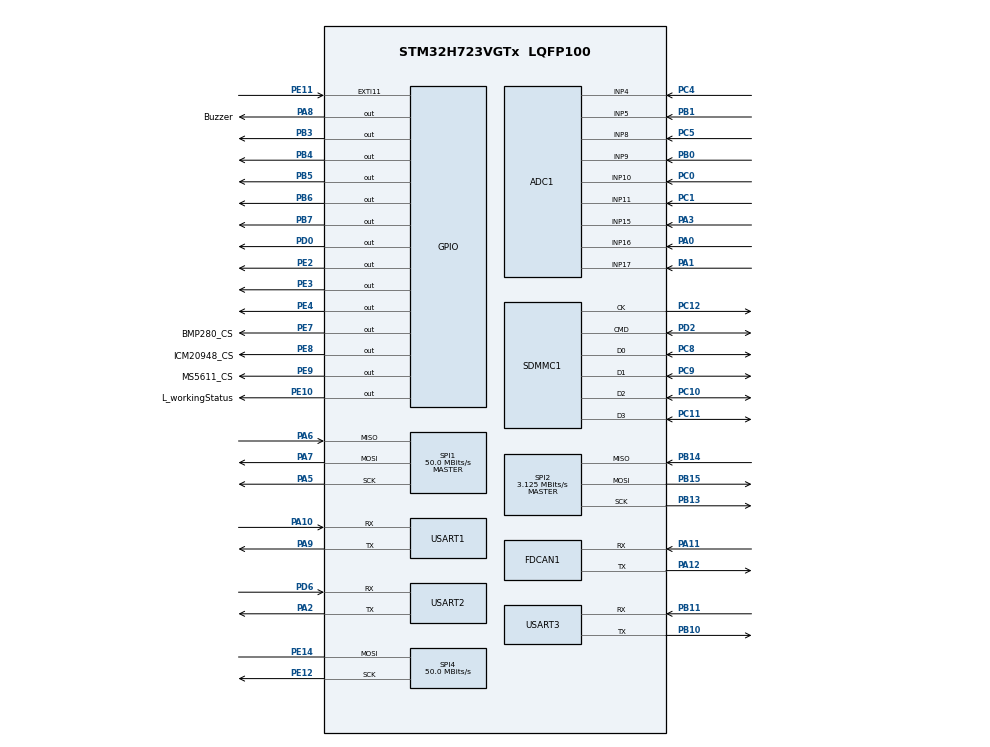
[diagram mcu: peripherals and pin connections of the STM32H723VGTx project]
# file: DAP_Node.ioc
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ADC1.Channel-1\#ChannelRegularConversion=ADC_CHANNEL_10
ADC1.NbrOfConversionFlag=1
ADC1.OffsetNumber-1\#ChannelRegularConversion=ADC_OFFSET_NONE
ADC1.OffsetSignedSaturation-1\#ChannelRegularConversion=DISABLE
ADC1.Rank-1\#ChannelRegularConversion=1
ADC1.SamplingTime-1\#ChannelRegularConversion=ADC_SAMPLETIME_1CYCLE_5
ADC1.master=1
ADC2.Channel-1\#ChannelRegularConversion=ADC_CHANNEL_11
ADC2.NbrOfConversionFlag=1
ADC2.OffsetNumber-1\#ChannelRegularConversion=ADC_OFFSET_NONE
ADC2.OffsetSignedSaturation-1\#ChannelRegularConversion=DISABLE
ADC2.Rank-1\#ChannelRegularConversion=1
ADC2.Resolution=ADC_RESOLUTION_16B
ADC2.SamplingTime-1\#ChannelRegularConversion=ADC_SAMPLETIME_1CYCLE_5
CORTEX_M7.default_mode_Activation=1
FDCAN1.CalculateBaudRateNominal=520833
FDCAN1.CalculateTimeBitNominal=1920
FDCAN1.CalculateTimeQuantumNominal=640.0
Mcu.Family=STM32H7
Mcu.Name=STM32H723VGTx
Mcu.Package=LQFP100
NVIC.PriorityGroup=NVIC_PRIORITYGROUP_4
PA0.Mode=IN16-Single-Ended
PA0.Signal=ADC1_INP16
PA1.Mode=IN17-Single-Ended
PA1.Signal=ADC1_INP17
PA10.Mode=Asynchronous
PA10.Signal=USART1_RX
PA11.Mode=FDCAN_Activate
PA11.Signal=FDCAN1_RX
PA12.Mode=FDCAN_Activate
PA12.Signal=FDCAN1_TX
PA13(JTMS/SWDIO).Mode=Serial_Wire
PA13(JTMS/SWDIO).Signal=DEBUG_JTMS-SWDIO
PA14(JTCK/SWCLK).Mode=Serial_Wire
PA14(JTCK/SWCLK).Signal=DEBUG_JTCK-SWCLK
PA2.Mode=Asynchronous
PA2.Signal=USART2_TX
PA3.Signal=ADCx_INP15
PA5.GPIO_Speed=GPIO_SPEED_FREQ_VERY_HIGH
PA5.Mode=Full_Duplex_Master
PA5.Signal=SPI1_SCK
PA6.GPIO_Speed=GPIO_SPEED_FREQ_VERY_HIGH
PA6.Mode=Full_Duplex_Master
PA6.Signal=SPI1_MISO
PA7.GPIO_Speed=GPIO_SPEED_FREQ_VERY_HIGH
PA7.Mode=Full_Duplex_Master
PA7.Signal=SPI1_MOSI
PA8.GPIO_Label=Buzzer
PA8.Signal=GPIO_Output
PA9.Mode=Asynchronous
PA9.Signal=USART1_TX
PB0.Signal=ADCx_INP9
PB1.Signal=ADCx_INP5
PB10.Mode=Asynchronous
PB10.Signal=USART3_TX
PB11.Mode=Asynchronous
PB11.Signal=USART3_RX
PB13.GPIO_Speed=GPIO_SPEED_FREQ_VERY_HIGH
PB13.Mode=Full_Duplex_Master
PB13.Signal=SPI2_SCK
PB14.GPIO_Speed=GPIO_SPEED_FREQ_VERY_HIGH
PB14.Mode=Full_Duplex_Master
PB14.Signal=SPI2_MISO
PB15.GPIO_Speed=GPIO_SPEED_FREQ_VERY_HIGH
PB15.Mode=Full_Duplex_Master
PB15.Signal=SPI2_MOSI
PB3(JTDO/TRACESWO).Signal=GPIO_Output
PB4(NJTRST).Signal=GPIO_Output
PB5.Signal=GPIO_Output
PB6.Signal=GPIO_Output
PB7.Signal=GPIO_Output
PC0.Signal=ADCx_INP10
PC1.Signal=SharedAnalog_PC1
PC10.Mode=SD_4_bits_Wide_bus
PC10.Signal=SDMMC1_D2
PC11.Mode=SD_4_bits_Wide_bus
PC11.Signal=SDMMC1_D3
PC12.Mode=SD_4_bits_Wide_bus
PC12.Signal=SDMMC1_CK
PC14-OSC32_IN.Mode=LSE-External-Oscillator
PC14-OSC32_IN.Signal=RCC_OSC32_IN
PC15-OSC32_OUT.Mode=LSE-External-Oscillator
PC15-OSC32_OUT.Signal=RCC_OSC32_OUT
PC4.Signal=ADCx_INP4
PC5.Signal=ADCx_INP8
PC8.Mode=SD_4_bits_Wide_bus
PC8.Signal=SDMMC1_D0
PC9.Mode=SD_4_bits_Wide_bus
PC9.Signal=SDMMC1_D1
PD0.GPIO_Speed=GPIO_SPEED_FREQ_VERY_HIGH
PD0.PinState=GPIO_PIN_SET
PD0.Signal=GPIO_Output
PD2.Mode=SD_4_bits_Wide_bus
PD2.Signal=SDMMC1_CMD
PD6.Mode=Asynchronous
PD6.Signal=USART2_RX
PE10.GPIO_Label=L_workingStatus
PE10.Signal=GPIO_Output
PE11.Signal=GPXTI11
PE12.Mode=Simplex_Bidirectional_Master
PE12.Signal=SPI4_SCK
PE14.Mode=Simplex_Bidirectional_Master
PE14.Signal=SPI4_MOSI
PE2.Signal=GPIO_Output
PE3.Signal=GPIO_Output
PE4.Signal=GPIO_Output
PE7.GPIO_Label=BMP280_CS
PE7.Signal=GPIO_Output
PE8.GPIO_Label=ICM20948_CS
PE8.Signal=GPIO_Output
PE9.GPIO_Label=MS5611_CS
PE9.Signal=GPIO_Output
PH0-OSC_IN.Mode=HSE-External-Oscillator
PH0-OSC_IN.Signal=RCC_OSC_IN
PH1-OSC_OUT.Mode=HSE-External-Oscillator
PH1-OSC_OUT.Signal=RCC_OSC_OUT
ProjectManager.HeapSize=0x200
ProjectManager.StackSize=0x400
ProjectManager.TargetToolchain=STM32CubeIDE
RCC.ADCFreq_Value=100000000
RCC.APB1Freq_Value=50000000
RCC.APB2Freq_Value=100000000
RCC.APB3Freq_Value=100000000
RCC.APB4Freq_Value=100000000
RCC.CortexFreq_Value=200000000
RCC.D1PPRE=RCC_APB3_DIV2
RCC.D2PPRE1=RCC_APB1_DIV4
RCC.D2PPRE2=RCC_APB2_DIV2
RCC.D3PPRE=RCC_APB4_DIV2
RCC.DIVM1=2
RCC.DIVM2=2
RCC.DIVN1=16
RCC.DIVN2=16
RCC.DIVP1=1
RCC.DIVR1=20
RCC.FDCANCLockSelection=RCC_FDCANCLKSOURCE_HSE
RCC.HCLKFreq_Value=200000000
RCC.HSE_VALUE=25000000
RCC.PLL2FRACN=0
RCC.PLL3FRACN=0
RCC.PLL3_VCI_Range-AdvancedSettings=RCC_PLL3VCIRANGE_3
RCC.PLLFRACN=0
RCC.PLLSourceVirtual=RCC_PLLSOURCE_HSE
RCC.SYSCLKFreq_VALUE=200000000
RCC.SYSCLKSource=RCC_SYSCLKSOURCE_PLLCLK
RCC.USBFreq_Value=100000000
SDMMC1.ClockDiv=100
SH.ADCx_INP10.0=ADC1_INP10,IN10-Single-Ended
SH.ADCx_INP15.0=ADC1_INP15,IN15-Single-Ended
SH.ADCx_INP4.0=ADC1_INP4,IN4-Single-Ended
SH.ADCx_INP5.0=ADC1_INP5,IN5-Single-Ended
SH.ADCx_INP8.0=ADC1_INP8,IN8-Single-Ended
SH.ADCx_INP9.0=ADC1_INP9,IN9-Single-Ended
SH.SharedAnalog_PC1.0=ADC1_INN10
SH.SharedAnalog_PC1.1=ADC1_INP11,IN11-Single-Ended
SH.SharedAnalog_PC1.2=ADC2_INP11,IN11-Single-Ended
SPI1.CalculateBaudRate=50.0 MBits/s
SPI1.Direction=SPI_DIRECTION_2LINES
SPI1.Mode=SPI_MODE_MASTER
SPI1.VirtualType=VM_MASTER
SPI2.BaudRatePrescaler=SPI_BAUDRATEPRESCALER_32
SPI2.CLKPhase=SPI_PHASE_2EDGE
SPI2.CLKPolarity=SPI_POLARITY_LOW
SPI2.CalculateBaudRate=3.125 MBits/s
SPI2.DataSize=SPI_DATASIZE_8BIT
SPI2.Direction=SPI_DIRECTION_2LINES
SPI2.Mode=SPI_MODE_MASTER
SPI2.NSSPolarity=SPI_NSS_POLARITY_HIGH
SPI2.VirtualType=VM_MASTER
SPI4.CalculateBaudRate=50.0 MBits/s
SPI4.Direction=SPI_DIRECTION_1LINE
SPI4.Mode=SPI_MODE_MASTER
SPI4.VirtualType=VM_MASTER
USART1.VirtualMode-Asynchronous=VM_ASYNC
USART2.VirtualMode-Asynchronous=VM_ASYNC
USART3.VirtualMode-Asynchronous=VM_ASYNC
VP_FATFS_VS_SDIO.Mode=SDIO
VP_MEMORYMAP_VS_MEMORYMAP.Mode=CurAppReg
board=custom

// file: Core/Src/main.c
/* USER CODE BEGIN Header */
/**
  ******************************************************************************
  * @file           : main.c
  * @brief          : Main program body
  ******************************************************************************
  * @attention
  *
  * Copyright (c) 2026 STMicroelectronics.
  * All rights reserved.
  *
  * This software is licensed under terms that can be found in the LICENSE file
  * in the root directory of this software component.
  * If no LICENSE file comes with this software, it is provided AS-IS.
  *
  ******************************************************************************
  */
/* USER CODE END Header */
#include "main.h"
#include "adc.h"
#include "fatfs.h"
#include "fdcan.h"
#include "sdmmc.h"
#include "spi.h"
#include "usart.h"
#include "gpio.h"

void SystemClock_Config(void);
void PeriphCommonClock_Config(void);
static void MPU_Config(void);

int main(void)
{

  /* MPU Configuration--------------------------------------------------------*/
  MPU_Config();

  /* MCU Configuration--------------------------------------------------------*/

  /* Reset of all peripherals, Initializes the Flash interface and the Systick. */
  HAL_Init();

  /* Configure the system clock */
  SystemClock_Config();

  /* Configure the peripherals common clocks */
  PeriphCommonClock_Config();

  /* Initialize all configured peripherals */
  MX_GPIO_Init();
  MX_USART1_UART_Init();
  MX_FDCAN1_Init();
  MX_SPI1_Init();
  MX_SPI2_Init();
  MX_USART2_UART_Init();
  MX_SDMMC1_SD_Init();
  MX_FATFS_Init();
  MX_SPI4_Init();
  MX_USART3_UART_Init();
  MX_ADC1_Init();
  MX_ADC2_Init();

  /* Infinite loop */
  while (1)
  {

    /* USER CODE BEGIN 3 */
	  HAL_GPIO_TogglePin(GPIOE, GPIO_PIN_3);
	  HAL_Delay(1000);
  }
  /* USER CODE END 3 */
}

void SystemClock_Config(void)
{
  RCC_OscInitTypeDef RCC_OscInitStruct = {0};
  RCC_ClkInitTypeDef RCC_ClkInitStruct = {0};

  /** Supply configuration update enable
  */
  HAL_PWREx_ConfigSupply(PWR_LDO_SUPPLY);

  /** Configure the main internal regulator output voltage
  */
  __HAL_PWR_VOLTAGESCALING_CONFIG(PWR_REGULATOR_VOLTAGE_SCALE0);

  while(!__HAL_PWR_GET_FLAG(PWR_FLAG_VOSRDY)) {}

  /** Initializes the RCC Oscillators according to the specified parameters
  * in the RCC_OscInitTypeDef structure.
  */
  RCC_OscInitStruct.OscillatorType = RCC_OSCILLATORTYPE_HSE;
  RCC_OscInitStruct.HSEState = RCC_HSE_ON;
  RCC_OscInitStruct.PLL.PLLState = RCC_PLL_ON;
  RCC_OscInitStruct.PLL.PLLSource = RCC_PLLSOURCE_HSE;
  RCC_OscInitStruct.PLL.PLLM = 5;
  RCC_OscInitStruct.PLL.PLLN = 110;
  RCC_OscInitStruct.PLL.PLLP = 1;
  RCC_OscInitStruct.PLL.PLLQ = 20;
  RCC_OscInitStruct.PLL.PLLR = 20;
  RCC_OscInitStruct.PLL.PLLRGE = RCC_PLL1VCIRANGE_2;
  RCC_OscInitStruct.PLL.PLLVCOSEL = RCC_PLL1VCOWIDE;
  RCC_OscInitStruct.PLL.PLLFRACN = 0;
  if (HAL_RCC_OscConfig(&RCC_OscInitStruct) != HAL_OK)
  {
    Error_Handler();
  }

  /** Initializes the CPU, AHB and APB buses clocks
  */
  RCC_ClkInitStruct.ClockType = RCC_CLOCKTYPE_HCLK|RCC_CLOCKTYPE_SYSCLK
                              |RCC_CLOCKTYPE_PCLK1|RCC_CLOCKTYPE_PCLK2
                              |RCC_CLOCKTYPE_D3PCLK1|RCC_CLOCKTYPE_D1PCLK1;
  RCC_ClkInitStruct.SYSCLKSource = RCC_SYSCLKSOURCE_PLLCLK;
  RCC_ClkInitStruct.SYSCLKDivider = RCC_SYSCLK_DIV1;
  RCC_ClkInitStruct.AHBCLKDivider = RCC_HCLK_DIV2;
  RCC_ClkInitStruct.APB3CLKDivider = RCC_APB3_DIV2;
  RCC_ClkInitStruct.APB1CLKDivider = RCC_APB1_DIV2;
  RCC_ClkInitStruct.APB2CLKDivider = RCC_APB2_DIV2;
  RCC_ClkInitStruct.APB4CLKDivider = RCC_APB4_DIV2;

  if (HAL_RCC_ClockConfig(&RCC_ClkInitStruct, FLASH_LATENCY_3) != HAL_OK)
  {
    Error_Handler();
  }
}

void PeriphCommonClock_Config(void)
{
  RCC_PeriphCLKInitTypeDef PeriphClkInitStruct = {0};

  /** Initializes the peripherals clock
  */
  PeriphClkInitStruct.PeriphClockSelection = RCC_PERIPHCLK_ADC;
  PeriphClkInitStruct.PLL2.PLL2M = 32;
  PeriphClkInitStruct.PLL2.PLL2N = 129;
  PeriphClkInitStruct.PLL2.PLL2P = 2;
  PeriphClkInitStruct.PLL2.PLL2Q = 2;
  PeriphClkInitStruct.PLL2.PLL2R = 2;
  PeriphClkInitStruct.PLL2.PLL2RGE = RCC_PLL2VCIRANGE_3;
  PeriphClkInitStruct.PLL2.PLL2VCOSEL = RCC_PLL2VCOWIDE;
  PeriphClkInitStruct.PLL2.PLL2FRACN = 0;
  PeriphClkInitStruct.AdcClockSelection = RCC_ADCCLKSOURCE_PLL2;
  if (HAL_RCCEx_PeriphCLKConfig(&PeriphClkInitStruct) != HAL_OK)
  {
    Error_Handler();
  }
}

 /* MPU Configuration */

void MPU_Config(void)
{
  MPU_Region_InitTypeDef MPU_InitStruct = {0};

  /* Disables the MPU */
  HAL_MPU_Disable();

  /** Initializes and configures the Region and the memory to be protected
  */
  MPU_InitStruct.Enable = MPU_REGION_ENABLE;
  MPU_InitStruct.Number = MPU_REGION_NUMBER0;
  MPU_InitStruct.BaseAddress = 0x0;
  MPU_InitStruct.Size = MPU_REGION_SIZE_4GB;
  MPU_InitStruct.SubRegionDisable = 0x87;
  MPU_InitStruct.TypeExtField = MPU_TEX_LEVEL0;
  MPU_InitStruct.AccessPermission = MPU_REGION_NO_ACCESS;
  MPU_InitStruct.DisableExec = MPU_INSTRUCTION_ACCESS_DISABLE;
  MPU_InitStruct.IsShareable = MPU_ACCESS_SHAREABLE;
  MPU_InitStruct.IsCacheable = MPU_ACCESS_NOT_CACHEABLE;
  MPU_InitStruct.IsBufferable = MPU_ACCESS_NOT_BUFFERABLE;

  HAL_MPU_ConfigRegion(&MPU_InitStruct);
  /* Enables the MPU */
  HAL_MPU_Enable(MPU_PRIVILEGED_DEFAULT);

}

void Error_Handler(void)
{
  __disable_irq();
  while (1)
  {
  }
}
